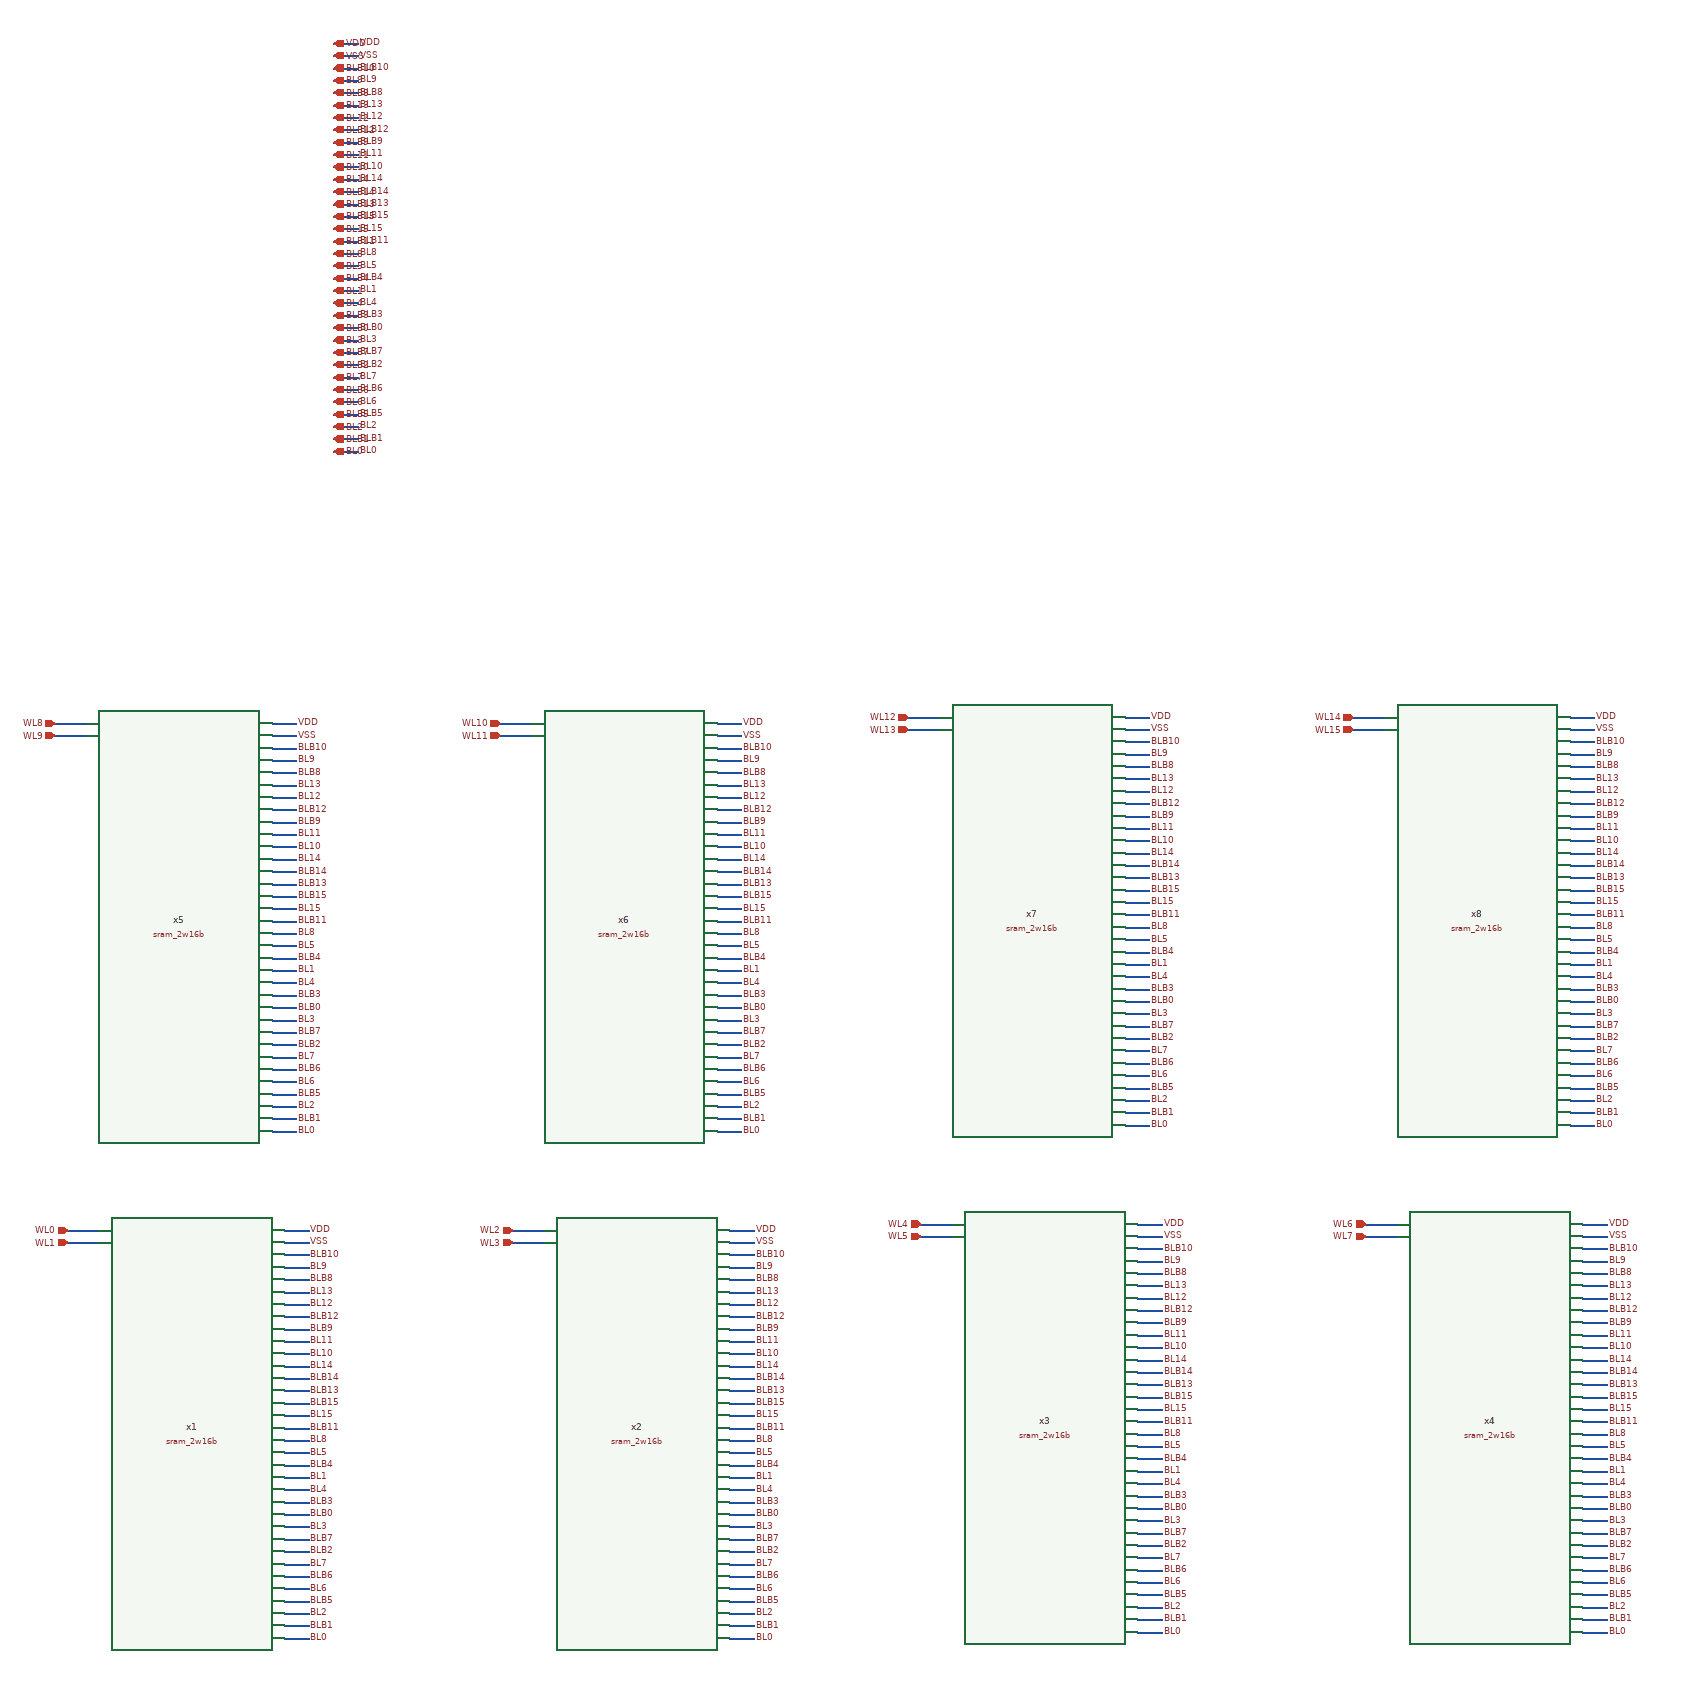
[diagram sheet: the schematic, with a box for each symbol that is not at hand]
v {xschem version=3.4.8RC file_version=1.3}
G {}
K {}
V {}
S {}
F {}
E {}
N 90 -730 140 -730 {lab=WL0}
N 90 -710 140 -710 {lab=WL1}
N 440 -730 480 -730 {lab=VDD}
N 440 -710 480 -710 {lab=VSS}
N 440 -690 480 -690 {lab=BLB10}
N 440 -670 480 -670 {lab=BL9}
N 440 -650 480 -650 {lab=BLB8}
N 440 -630 480 -630 {lab=BL13}
N 440 -610 480 -610 {lab=BL12}
N 440 -590 480 -590 {lab=BLB12}
N 440 -570 480 -570 {lab=BLB9}
N 440 -550 480 -550 {lab=BL11}
N 440 -530 480 -530 {lab=BL10}
N 440 -510 480 -510 {lab=BL14}
N 440 -490 480 -490 {lab=BLB14}
N 440 -470 480 -470 {lab=BLB13}
N 440 -450 480 -450 {lab=BLB15}
N 440 -430 480 -430 {lab=BL15}
N 440 -410 480 -410 {lab=BLB11}
N 440 -390 480 -390 {lab=BL8}
N 440 -370 480 -370 {lab=BL5}
N 440 -350 480 -350 {lab=BLB4}
N 440 -330 480 -330 {lab=BL1}
N 440 -310 480 -310 {lab=BL4}
N 440 -290 480 -290 {lab=BLB3}
N 440 -270 480 -270 {lab=BLB0}
N 440 -250 480 -250 {lab=BL3}
N 440 -230 480 -230 {lab=BLB7}
N 440 -210 480 -210 {lab=BLB2}
N 440 -190 480 -190 {lab=BL7}
N 440 -170 480 -170 {lab=BLB6}
N 440 -150 480 -150 {lab=BL6}
N 440 -130 480 -130 {lab=BLB5}
N 440 -110 480 -110 {lab=BL2}
N 440 -90 480 -90 {lab=BLB1}
N 440 -70 480 -70 {lab=BL0}
N 810 -730 860 -730 {lab=WL2}
N 810 -710 860 -710 {lab=WL3}
N 1160 -730 1200 -730 {lab=VDD}
N 1160 -710 1200 -710 {lab=VSS}
N 1160 -690 1200 -690 {lab=BLB10}
N 1160 -670 1200 -670 {lab=BL9}
N 1160 -650 1200 -650 {lab=BLB8}
N 1160 -630 1200 -630 {lab=BL13}
N 1160 -610 1200 -610 {lab=BL12}
N 1160 -590 1200 -590 {lab=BLB12}
N 1160 -570 1200 -570 {lab=BLB9}
N 1160 -550 1200 -550 {lab=BL11}
N 1160 -530 1200 -530 {lab=BL10}
N 1160 -510 1200 -510 {lab=BL14}
N 1160 -490 1200 -490 {lab=BLB14}
N 1160 -470 1200 -470 {lab=BLB13}
N 1160 -450 1200 -450 {lab=BLB15}
N 1160 -430 1200 -430 {lab=BL15}
N 1160 -410 1200 -410 {lab=BLB11}
N 1160 -390 1200 -390 {lab=BL8}
N 1160 -370 1200 -370 {lab=BL5}
N 1160 -350 1200 -350 {lab=BLB4}
N 1160 -330 1200 -330 {lab=BL1}
N 1160 -310 1200 -310 {lab=BL4}
N 1160 -290 1200 -290 {lab=BLB3}
N 1160 -270 1200 -270 {lab=BLB0}
N 1160 -250 1200 -250 {lab=BL3}
N 1160 -230 1200 -230 {lab=BLB7}
N 1160 -210 1200 -210 {lab=BLB2}
N 1160 -190 1200 -190 {lab=BL7}
N 1160 -170 1200 -170 {lab=BLB6}
N 1160 -150 1200 -150 {lab=BL6}
N 1160 -130 1200 -130 {lab=BLB5}
N 1160 -110 1200 -110 {lab=BL2}
N 1160 -90 1200 -90 {lab=BLB1}
N 1160 -70 1200 -70 {lab=BL0}
N 1470 -740 1520 -740 {lab=WL4}
N 1470 -720 1520 -720 {lab=WL5}
N 1820 -740 1860 -740 {lab=VDD}
N 1820 -720 1860 -720 {lab=VSS}
N 1820 -700 1860 -700 {lab=BLB10}
N 1820 -680 1860 -680 {lab=BL9}
N 1820 -660 1860 -660 {lab=BLB8}
N 1820 -640 1860 -640 {lab=BL13}
N 1820 -620 1860 -620 {lab=BL12}
N 1820 -600 1860 -600 {lab=BLB12}
N 1820 -580 1860 -580 {lab=BLB9}
N 1820 -560 1860 -560 {lab=BL11}
N 1820 -540 1860 -540 {lab=BL10}
N 1820 -520 1860 -520 {lab=BL14}
N 1820 -500 1860 -500 {lab=BLB14}
N 1820 -480 1860 -480 {lab=BLB13}
N 1820 -460 1860 -460 {lab=BLB15}
N 1820 -440 1860 -440 {lab=BL15}
N 1820 -420 1860 -420 {lab=BLB11}
N 1820 -400 1860 -400 {lab=BL8}
N 1820 -380 1860 -380 {lab=BL5}
N 1820 -360 1860 -360 {lab=BLB4}
N 1820 -340 1860 -340 {lab=BL1}
N 1820 -320 1860 -320 {lab=BL4}
N 1820 -300 1860 -300 {lab=BLB3}
N 1820 -280 1860 -280 {lab=BLB0}
N 1820 -260 1860 -260 {lab=BL3}
N 1820 -240 1860 -240 {lab=BLB7}
N 1820 -220 1860 -220 {lab=BLB2}
N 1820 -200 1860 -200 {lab=BL7}
N 1820 -180 1860 -180 {lab=BLB6}
N 1820 -160 1860 -160 {lab=BL6}
N 1820 -140 1860 -140 {lab=BLB5}
N 1820 -120 1860 -120 {lab=BL2}
N 1820 -100 1860 -100 {lab=BLB1}
N 1820 -80 1860 -80 {lab=BL0}
N 2190 -740 2240 -740 {lab=WL6}
N 2190 -720 2240 -720 {lab=WL1}
N 2540 -740 2580 -740 {lab=VDD}
N 2540 -720 2580 -720 {lab=VSS}
N 2540 -700 2580 -700 {lab=BLB10}
N 2540 -680 2580 -680 {lab=BL9}
N 2540 -660 2580 -660 {lab=BLB8}
N 2540 -640 2580 -640 {lab=BL13}
N 2540 -620 2580 -620 {lab=BL12}
N 2540 -600 2580 -600 {lab=BLB12}
N 2540 -580 2580 -580 {lab=BLB9}
N 2540 -560 2580 -560 {lab=BL11}
N 2540 -540 2580 -540 {lab=BL10}
N 2540 -520 2580 -520 {lab=BL14}
N 2540 -500 2580 -500 {lab=BLB14}
N 2540 -480 2580 -480 {lab=BLB13}
N 2540 -460 2580 -460 {lab=BLB15}
N 2540 -440 2580 -440 {lab=BL15}
N 2540 -420 2580 -420 {lab=BLB11}
N 2540 -400 2580 -400 {lab=BL8}
N 2540 -380 2580 -380 {lab=BL5}
N 2540 -360 2580 -360 {lab=BLB4}
N 2540 -340 2580 -340 {lab=BL1}
N 2540 -320 2580 -320 {lab=BL4}
N 2540 -300 2580 -300 {lab=BLB3}
N 2540 -280 2580 -280 {lab=BLB0}
N 2540 -260 2580 -260 {lab=BL3}
N 2540 -240 2580 -240 {lab=BLB7}
N 2540 -220 2580 -220 {lab=BLB2}
N 2540 -200 2580 -200 {lab=BL7}
N 2540 -180 2580 -180 {lab=BLB6}
N 2540 -160 2580 -160 {lab=BL6}
N 2540 -140 2580 -140 {lab=BLB5}
N 2540 -120 2580 -120 {lab=BL2}
N 2540 -100 2580 -100 {lab=BLB1}
N 2540 -80 2580 -80 {lab=BL0}
N 70 -1550 120 -1550 {lab=WL0}
N 70 -1530 120 -1530 {lab=WL1}
N 420 -1550 460 -1550 {lab=VDD}
N 420 -1530 460 -1530 {lab=VSS}
N 420 -1510 460 -1510 {lab=BLB10}
N 420 -1490 460 -1490 {lab=BL9}
N 420 -1470 460 -1470 {lab=BLB8}
N 420 -1450 460 -1450 {lab=BL13}
N 420 -1430 460 -1430 {lab=BL12}
N 420 -1410 460 -1410 {lab=BLB12}
N 420 -1390 460 -1390 {lab=BLB9}
N 420 -1370 460 -1370 {lab=BL11}
N 420 -1350 460 -1350 {lab=BL10}
N 420 -1330 460 -1330 {lab=BL14}
N 420 -1310 460 -1310 {lab=BLB14}
N 420 -1290 460 -1290 {lab=BLB13}
N 420 -1270 460 -1270 {lab=BLB15}
N 420 -1250 460 -1250 {lab=BL15}
N 420 -1230 460 -1230 {lab=BLB11}
N 420 -1210 460 -1210 {lab=BL8}
N 420 -1190 460 -1190 {lab=BL5}
N 420 -1170 460 -1170 {lab=BLB4}
N 420 -1150 460 -1150 {lab=BL1}
N 420 -1130 460 -1130 {lab=BL4}
N 420 -1110 460 -1110 {lab=BLB3}
N 420 -1090 460 -1090 {lab=BLB0}
N 420 -1070 460 -1070 {lab=BL3}
N 420 -1050 460 -1050 {lab=BLB7}
N 420 -1030 460 -1030 {lab=BLB2}
N 420 -1010 460 -1010 {lab=BL7}
N 420 -990 460 -990 {lab=BLB6}
N 420 -970 460 -970 {lab=BL6}
N 420 -950 460 -950 {lab=BLB5}
N 420 -930 460 -930 {lab=BL2}
N 420 -910 460 -910 {lab=BLB1}
N 420 -890 460 -890 {lab=BL0}
N 790 -1550 840 -1550 {lab=WL2}
N 790 -1530 840 -1530 {lab=WL3}
N 1140 -1550 1180 -1550 {lab=VDD}
N 1140 -1530 1180 -1530 {lab=VSS}
N 1140 -1510 1180 -1510 {lab=BLB10}
N 1140 -1490 1180 -1490 {lab=BL9}
N 1140 -1470 1180 -1470 {lab=BLB8}
N 1140 -1450 1180 -1450 {lab=BL13}
N 1140 -1430 1180 -1430 {lab=BL12}
N 1140 -1410 1180 -1410 {lab=BLB12}
N 1140 -1390 1180 -1390 {lab=BLB9}
N 1140 -1370 1180 -1370 {lab=BL11}
N 1140 -1350 1180 -1350 {lab=BL10}
N 1140 -1330 1180 -1330 {lab=BL14}
N 1140 -1310 1180 -1310 {lab=BLB14}
N 1140 -1290 1180 -1290 {lab=BLB13}
N 1140 -1270 1180 -1270 {lab=BLB15}
N 1140 -1250 1180 -1250 {lab=BL15}
N 1140 -1230 1180 -1230 {lab=BLB11}
N 1140 -1210 1180 -1210 {lab=BL8}
N 1140 -1190 1180 -1190 {lab=BL5}
N 1140 -1170 1180 -1170 {lab=BLB4}
N 1140 -1150 1180 -1150 {lab=BL1}
N 1140 -1130 1180 -1130 {lab=BL4}
N 1140 -1110 1180 -1110 {lab=BLB3}
N 1140 -1090 1180 -1090 {lab=BLB0}
N 1140 -1070 1180 -1070 {lab=BL3}
N 1140 -1050 1180 -1050 {lab=BLB7}
N 1140 -1030 1180 -1030 {lab=BLB2}
N 1140 -1010 1180 -1010 {lab=BL7}
N 1140 -990 1180 -990 {lab=BLB6}
N 1140 -970 1180 -970 {lab=BL6}
N 1140 -950 1180 -950 {lab=BLB5}
N 1140 -930 1180 -930 {lab=BL2}
N 1140 -910 1180 -910 {lab=BLB1}
N 1140 -890 1180 -890 {lab=BL0}
N 1450 -1560 1500 -1560 {lab=WL4}
N 1450 -1540 1500 -1540 {lab=WL5}
N 1800 -1560 1840 -1560 {lab=VDD}
N 1800 -1540 1840 -1540 {lab=VSS}
N 1800 -1520 1840 -1520 {lab=BLB10}
N 1800 -1500 1840 -1500 {lab=BL9}
N 1800 -1480 1840 -1480 {lab=BLB8}
N 1800 -1460 1840 -1460 {lab=BL13}
N 1800 -1440 1840 -1440 {lab=BL12}
N 1800 -1420 1840 -1420 {lab=BLB12}
N 1800 -1400 1840 -1400 {lab=BLB9}
N 1800 -1380 1840 -1380 {lab=BL11}
N 1800 -1360 1840 -1360 {lab=BL10}
N 1800 -1340 1840 -1340 {lab=BL14}
N 1800 -1320 1840 -1320 {lab=BLB14}
N 1800 -1300 1840 -1300 {lab=BLB13}
N 1800 -1280 1840 -1280 {lab=BLB15}
N 1800 -1260 1840 -1260 {lab=BL15}
N 1800 -1240 1840 -1240 {lab=BLB11}
N 1800 -1220 1840 -1220 {lab=BL8}
N 1800 -1200 1840 -1200 {lab=BL5}
N 1800 -1180 1840 -1180 {lab=BLB4}
N 1800 -1160 1840 -1160 {lab=BL1}
N 1800 -1140 1840 -1140 {lab=BL4}
N 1800 -1120 1840 -1120 {lab=BLB3}
N 1800 -1100 1840 -1100 {lab=BLB0}
N 1800 -1080 1840 -1080 {lab=BL3}
N 1800 -1060 1840 -1060 {lab=BLB7}
N 1800 -1040 1840 -1040 {lab=BLB2}
N 1800 -1020 1840 -1020 {lab=BL7}
N 1800 -1000 1840 -1000 {lab=BLB6}
N 1800 -980 1840 -980 {lab=BL6}
N 1800 -960 1840 -960 {lab=BLB5}
N 1800 -940 1840 -940 {lab=BL2}
N 1800 -920 1840 -920 {lab=BLB1}
N 1800 -900 1840 -900 {lab=BL0}
N 2170 -1560 2220 -1560 {lab=WL6}
N 2170 -1540 2220 -1540 {lab=WL1}
N 2520 -1560 2560 -1560 {lab=VDD}
N 2520 -1540 2560 -1540 {lab=VSS}
N 2520 -1520 2560 -1520 {lab=BLB10}
N 2520 -1500 2560 -1500 {lab=BL9}
N 2520 -1480 2560 -1480 {lab=BLB8}
N 2520 -1460 2560 -1460 {lab=BL13}
N 2520 -1440 2560 -1440 {lab=BL12}
N 2520 -1420 2560 -1420 {lab=BLB12}
N 2520 -1400 2560 -1400 {lab=BLB9}
N 2520 -1380 2560 -1380 {lab=BL11}
N 2520 -1360 2560 -1360 {lab=BL10}
N 2520 -1340 2560 -1340 {lab=BL14}
N 2520 -1320 2560 -1320 {lab=BLB14}
N 2520 -1300 2560 -1300 {lab=BLB13}
N 2520 -1280 2560 -1280 {lab=BLB15}
N 2520 -1260 2560 -1260 {lab=BL15}
N 2520 -1240 2560 -1240 {lab=BLB11}
N 2520 -1220 2560 -1220 {lab=BL8}
N 2520 -1200 2560 -1200 {lab=BL5}
N 2520 -1180 2560 -1180 {lab=BLB4}
N 2520 -1160 2560 -1160 {lab=BL1}
N 2520 -1140 2560 -1140 {lab=BL4}
N 2520 -1120 2560 -1120 {lab=BLB3}
N 2520 -1100 2560 -1100 {lab=BLB0}
N 2520 -1080 2560 -1080 {lab=BL3}
N 2520 -1060 2560 -1060 {lab=BLB7}
N 2520 -1040 2560 -1040 {lab=BLB2}
N 2520 -1020 2560 -1020 {lab=BL7}
N 2520 -1000 2560 -1000 {lab=BLB6}
N 2520 -980 2560 -980 {lab=BL6}
N 2520 -960 2560 -960 {lab=BLB5}
N 2520 -940 2560 -940 {lab=BL2}
N 2520 -920 2560 -920 {lab=BLB1}
N 2520 -900 2560 -900 {lab=BL0}
N 520 -2650 560 -2650 {lab=VDD}
N 520 -2630 560 -2630 {lab=VSS}
N 520 -2610 560 -2610 {lab=BLB10}
N 520 -2590 560 -2590 {lab=BL9}
N 520 -2570 560 -2570 {lab=BLB8}
N 520 -2550 560 -2550 {lab=BL13}
N 520 -2530 560 -2530 {lab=BL12}
N 520 -2510 560 -2510 {lab=BLB12}
N 520 -2490 560 -2490 {lab=BLB9}
N 520 -2470 560 -2470 {lab=BL11}
N 520 -2450 560 -2450 {lab=BL10}
N 520 -2430 560 -2430 {lab=BL14}
N 520 -2410 560 -2410 {lab=BLB14}
N 520 -2390 560 -2390 {lab=BLB13}
N 520 -2370 560 -2370 {lab=BLB15}
N 520 -2350 560 -2350 {lab=BL15}
N 520 -2330 560 -2330 {lab=BLB11}
N 520 -2310 560 -2310 {lab=BL8}
N 520 -2290 560 -2290 {lab=BL5}
N 520 -2270 560 -2270 {lab=BLB4}
N 520 -2250 560 -2250 {lab=BL1}
N 520 -2230 560 -2230 {lab=BL4}
N 520 -2210 560 -2210 {lab=BLB3}
N 520 -2190 560 -2190 {lab=BLB0}
N 520 -2170 560 -2170 {lab=BL3}
N 520 -2150 560 -2150 {lab=BLB7}
N 520 -2130 560 -2130 {lab=BLB2}
N 520 -2110 560 -2110 {lab=BL7}
N 520 -2090 560 -2090 {lab=BLB6}
N 520 -2070 560 -2070 {lab=BL6}
N 520 -2050 560 -2050 {lab=BLB5}
N 520 -2030 560 -2030 {lab=BL2}
N 520 -2010 560 -2010 {lab=BLB1}
N 520 -1990 560 -1990 {lab=BL0}
C {sram_2w16b.sym} 290 -400 0 0 {name=x1}
C {devices/ipin.sym} 90 -730 0 0 {name=p1 lab=WL0}
C {devices/ipin.sym} 90 -710 0 0 {name=p2 lab=WL1}
C {devices/lab_pin.sym} 480 -730 0 1 {name=p3 sig_type=std_logic lab=VDD}
C {devices/lab_pin.sym} 480 -710 0 1 {name=p4 sig_type=std_logic lab=VSS}
C {devices/lab_pin.sym} 480 -690 0 1 {name=p5 sig_type=std_logic lab=BLB10}
C {devices/lab_pin.sym} 480 -670 0 1 {name=p6 sig_type=std_logic lab=BL9}
C {devices/lab_pin.sym} 480 -650 0 1 {name=p7 sig_type=std_logic lab=BLB8}
C {devices/lab_pin.sym} 480 -630 0 1 {name=p8 sig_type=std_logic lab=BL13}
C {devices/lab_pin.sym} 480 -610 0 1 {name=p9 sig_type=std_logic lab=BL12}
C {devices/lab_pin.sym} 480 -590 0 1 {name=p10 sig_type=std_logic lab=BLB12}
C {devices/lab_pin.sym} 480 -570 0 1 {name=p11 sig_type=std_logic lab=BLB9}
C {devices/lab_pin.sym} 480 -550 0 1 {name=p12 sig_type=std_logic lab=BL11}
C {devices/lab_pin.sym} 480 -530 0 1 {name=p13 sig_type=std_logic lab=BL10}
C {devices/lab_pin.sym} 480 -510 0 1 {name=p14 sig_type=std_logic lab=BL14}
C {devices/lab_pin.sym} 480 -490 0 1 {name=p15 sig_type=std_logic lab=BLB14}
C {devices/lab_pin.sym} 480 -470 0 1 {name=p16 sig_type=std_logic lab=BLB13}
C {devices/lab_pin.sym} 480 -450 0 1 {name=p17 sig_type=std_logic lab=BLB15}
C {devices/lab_pin.sym} 480 -430 0 1 {name=p18 sig_type=std_logic lab=BL15}
C {devices/lab_pin.sym} 480 -410 0 1 {name=p19 sig_type=std_logic lab=BLB11}
C {devices/lab_pin.sym} 480 -390 0 1 {name=p20 sig_type=std_logic lab=BL8}
C {devices/lab_pin.sym} 480 -370 0 1 {name=p21 sig_type=std_logic lab=BL5}
C {devices/lab_pin.sym} 480 -350 0 1 {name=p22 sig_type=std_logic lab=BLB4}
C {devices/lab_pin.sym} 480 -330 0 1 {name=p23 sig_type=std_logic lab=BL1}
C {devices/lab_pin.sym} 480 -310 0 1 {name=p24 sig_type=std_logic lab=BL4}
C {devices/lab_pin.sym} 480 -290 0 1 {name=p25 sig_type=std_logic lab=BLB3}
C {devices/lab_pin.sym} 480 -270 0 1 {name=p26 sig_type=std_logic lab=BLB0}
C {devices/lab_pin.sym} 480 -250 0 1 {name=p27 sig_type=std_logic lab=BL3}
C {devices/lab_pin.sym} 480 -230 0 1 {name=p28 sig_type=std_logic lab=BLB7}
C {devices/lab_pin.sym} 480 -210 0 1 {name=p29 sig_type=std_logic lab=BLB2}
C {devices/lab_pin.sym} 480 -190 0 1 {name=p30 sig_type=std_logic lab=BL7}
C {devices/lab_pin.sym} 480 -170 0 1 {name=p31 sig_type=std_logic lab=BLB6}
C {devices/lab_pin.sym} 480 -150 0 1 {name=p32 sig_type=std_logic lab=BL6}
C {devices/lab_pin.sym} 480 -130 0 1 {name=p33 sig_type=std_logic lab=BLB5}
C {devices/lab_pin.sym} 480 -110 0 1 {name=p34 sig_type=std_logic lab=BL2}
C {devices/lab_pin.sym} 480 -90 0 1 {name=p35 sig_type=std_logic lab=BLB1}
C {devices/lab_pin.sym} 480 -70 0 1 {name=p36 sig_type=std_logic lab=BL0}
C {sram_2w16b.sym} 1010 -400 0 0 {name=x2}
C {devices/ipin.sym} 810 -730 0 0 {name=p37 lab=WL2}
C {devices/ipin.sym} 810 -710 0 0 {name=p38 lab=WL3}
C {devices/lab_pin.sym} 1200 -730 0 1 {name=p39 sig_type=std_logic lab=VDD}
C {devices/lab_pin.sym} 1200 -710 0 1 {name=p40 sig_type=std_logic lab=VSS}
C {devices/lab_pin.sym} 1200 -690 0 1 {name=p41 sig_type=std_logic lab=BLB10}
C {devices/lab_pin.sym} 1200 -670 0 1 {name=p42 sig_type=std_logic lab=BL9}
C {devices/lab_pin.sym} 1200 -650 0 1 {name=p43 sig_type=std_logic lab=BLB8}
C {devices/lab_pin.sym} 1200 -630 0 1 {name=p44 sig_type=std_logic lab=BL13}
C {devices/lab_pin.sym} 1200 -610 0 1 {name=p45 sig_type=std_logic lab=BL12}
C {devices/lab_pin.sym} 1200 -590 0 1 {name=p46 sig_type=std_logic lab=BLB12}
C {devices/lab_pin.sym} 1200 -570 0 1 {name=p47 sig_type=std_logic lab=BLB9}
C {devices/lab_pin.sym} 1200 -550 0 1 {name=p48 sig_type=std_logic lab=BL11}
C {devices/lab_pin.sym} 1200 -530 0 1 {name=p49 sig_type=std_logic lab=BL10}
C {devices/lab_pin.sym} 1200 -510 0 1 {name=p50 sig_type=std_logic lab=BL14}
C {devices/lab_pin.sym} 1200 -490 0 1 {name=p51 sig_type=std_logic lab=BLB14}
C {devices/lab_pin.sym} 1200 -470 0 1 {name=p52 sig_type=std_logic lab=BLB13}
C {devices/lab_pin.sym} 1200 -450 0 1 {name=p53 sig_type=std_logic lab=BLB15}
C {devices/lab_pin.sym} 1200 -430 0 1 {name=p54 sig_type=std_logic lab=BL15}
C {devices/lab_pin.sym} 1200 -410 0 1 {name=p55 sig_type=std_logic lab=BLB11}
C {devices/lab_pin.sym} 1200 -390 0 1 {name=p56 sig_type=std_logic lab=BL8}
C {devices/lab_pin.sym} 1200 -370 0 1 {name=p57 sig_type=std_logic lab=BL5}
C {devices/lab_pin.sym} 1200 -350 0 1 {name=p58 sig_type=std_logic lab=BLB4}
C {devices/lab_pin.sym} 1200 -330 0 1 {name=p59 sig_type=std_logic lab=BL1}
C {devices/lab_pin.sym} 1200 -310 0 1 {name=p60 sig_type=std_logic lab=BL4}
C {devices/lab_pin.sym} 1200 -290 0 1 {name=p61 sig_type=std_logic lab=BLB3}
C {devices/lab_pin.sym} 1200 -270 0 1 {name=p62 sig_type=std_logic lab=BLB0}
C {devices/lab_pin.sym} 1200 -250 0 1 {name=p63 sig_type=std_logic lab=BL3}
C {devices/lab_pin.sym} 1200 -230 0 1 {name=p64 sig_type=std_logic lab=BLB7}
C {devices/lab_pin.sym} 1200 -210 0 1 {name=p65 sig_type=std_logic lab=BLB2}
C {devices/lab_pin.sym} 1200 -190 0 1 {name=p66 sig_type=std_logic lab=BL7}
C {devices/lab_pin.sym} 1200 -170 0 1 {name=p67 sig_type=std_logic lab=BLB6}
C {devices/lab_pin.sym} 1200 -150 0 1 {name=p68 sig_type=std_logic lab=BL6}
C {devices/lab_pin.sym} 1200 -130 0 1 {name=p69 sig_type=std_logic lab=BLB5}
C {devices/lab_pin.sym} 1200 -110 0 1 {name=p70 sig_type=std_logic lab=BL2}
C {devices/lab_pin.sym} 1200 -90 0 1 {name=p71 sig_type=std_logic lab=BLB1}
C {devices/lab_pin.sym} 1200 -70 0 1 {name=p72 sig_type=std_logic lab=BL0}
C {sram_2w16b.sym} 1670 -410 0 0 {name=x3}
C {devices/ipin.sym} 1470 -740 0 0 {name=p73 lab=WL4}
C {devices/ipin.sym} 1470 -720 0 0 {name=p74 lab=WL5}
C {devices/lab_pin.sym} 1860 -740 0 1 {name=p75 sig_type=std_logic lab=VDD}
C {devices/lab_pin.sym} 1860 -720 0 1 {name=p76 sig_type=std_logic lab=VSS}
C {devices/lab_pin.sym} 1860 -700 0 1 {name=p77 sig_type=std_logic lab=BLB10}
C {devices/lab_pin.sym} 1860 -680 0 1 {name=p78 sig_type=std_logic lab=BL9}
C {devices/lab_pin.sym} 1860 -660 0 1 {name=p79 sig_type=std_logic lab=BLB8}
C {devices/lab_pin.sym} 1860 -640 0 1 {name=p80 sig_type=std_logic lab=BL13}
C {devices/lab_pin.sym} 1860 -620 0 1 {name=p81 sig_type=std_logic lab=BL12}
C {devices/lab_pin.sym} 1860 -600 0 1 {name=p82 sig_type=std_logic lab=BLB12}
C {devices/lab_pin.sym} 1860 -580 0 1 {name=p83 sig_type=std_logic lab=BLB9}
C {devices/lab_pin.sym} 1860 -560 0 1 {name=p84 sig_type=std_logic lab=BL11}
C {devices/lab_pin.sym} 1860 -540 0 1 {name=p85 sig_type=std_logic lab=BL10}
C {devices/lab_pin.sym} 1860 -520 0 1 {name=p86 sig_type=std_logic lab=BL14}
C {devices/lab_pin.sym} 1860 -500 0 1 {name=p87 sig_type=std_logic lab=BLB14}
C {devices/lab_pin.sym} 1860 -480 0 1 {name=p88 sig_type=std_logic lab=BLB13}
C {devices/lab_pin.sym} 1860 -460 0 1 {name=p89 sig_type=std_logic lab=BLB15}
C {devices/lab_pin.sym} 1860 -440 0 1 {name=p90 sig_type=std_logic lab=BL15}
C {devices/lab_pin.sym} 1860 -420 0 1 {name=p91 sig_type=std_logic lab=BLB11}
C {devices/lab_pin.sym} 1860 -400 0 1 {name=p92 sig_type=std_logic lab=BL8}
C {devices/lab_pin.sym} 1860 -380 0 1 {name=p93 sig_type=std_logic lab=BL5}
C {devices/lab_pin.sym} 1860 -360 0 1 {name=p94 sig_type=std_logic lab=BLB4}
C {devices/lab_pin.sym} 1860 -340 0 1 {name=p95 sig_type=std_logic lab=BL1}
C {devices/lab_pin.sym} 1860 -320 0 1 {name=p96 sig_type=std_logic lab=BL4}
C {devices/lab_pin.sym} 1860 -300 0 1 {name=p97 sig_type=std_logic lab=BLB3}
C {devices/lab_pin.sym} 1860 -280 0 1 {name=p98 sig_type=std_logic lab=BLB0}
C {devices/lab_pin.sym} 1860 -260 0 1 {name=p99 sig_type=std_logic lab=BL3}
C {devices/lab_pin.sym} 1860 -240 0 1 {name=p100 sig_type=std_logic lab=BLB7}
C {devices/lab_pin.sym} 1860 -220 0 1 {name=p101 sig_type=std_logic lab=BLB2}
C {devices/lab_pin.sym} 1860 -200 0 1 {name=p102 sig_type=std_logic lab=BL7}
C {devices/lab_pin.sym} 1860 -180 0 1 {name=p103 sig_type=std_logic lab=BLB6}
C {devices/lab_pin.sym} 1860 -160 0 1 {name=p104 sig_type=std_logic lab=BL6}
C {devices/lab_pin.sym} 1860 -140 0 1 {name=p105 sig_type=std_logic lab=BLB5}
C {devices/lab_pin.sym} 1860 -120 0 1 {name=p106 sig_type=std_logic lab=BL2}
C {devices/lab_pin.sym} 1860 -100 0 1 {name=p107 sig_type=std_logic lab=BLB1}
C {devices/lab_pin.sym} 1860 -80 0 1 {name=p108 sig_type=std_logic lab=BL0}
C {sram_2w16b.sym} 2390 -410 0 0 {name=x4}
C {devices/ipin.sym} 2190 -740 0 0 {name=p109 lab=WL6}
C {devices/ipin.sym} 2190 -720 0 0 {name=p110 lab=WL7}
C {devices/lab_pin.sym} 2580 -740 0 1 {name=p111 sig_type=std_logic lab=VDD}
C {devices/lab_pin.sym} 2580 -720 0 1 {name=p112 sig_type=std_logic lab=VSS}
C {devices/lab_pin.sym} 2580 -700 0 1 {name=p113 sig_type=std_logic lab=BLB10}
C {devices/lab_pin.sym} 2580 -680 0 1 {name=p114 sig_type=std_logic lab=BL9}
C {devices/lab_pin.sym} 2580 -660 0 1 {name=p115 sig_type=std_logic lab=BLB8}
C {devices/lab_pin.sym} 2580 -640 0 1 {name=p116 sig_type=std_logic lab=BL13}
C {devices/lab_pin.sym} 2580 -620 0 1 {name=p117 sig_type=std_logic lab=BL12}
C {devices/lab_pin.sym} 2580 -600 0 1 {name=p118 sig_type=std_logic lab=BLB12}
C {devices/lab_pin.sym} 2580 -580 0 1 {name=p119 sig_type=std_logic lab=BLB9}
C {devices/lab_pin.sym} 2580 -560 0 1 {name=p120 sig_type=std_logic lab=BL11}
C {devices/lab_pin.sym} 2580 -540 0 1 {name=p121 sig_type=std_logic lab=BL10}
C {devices/lab_pin.sym} 2580 -520 0 1 {name=p122 sig_type=std_logic lab=BL14}
C {devices/lab_pin.sym} 2580 -500 0 1 {name=p123 sig_type=std_logic lab=BLB14}
C {devices/lab_pin.sym} 2580 -480 0 1 {name=p124 sig_type=std_logic lab=BLB13}
C {devices/lab_pin.sym} 2580 -460 0 1 {name=p125 sig_type=std_logic lab=BLB15}
C {devices/lab_pin.sym} 2580 -440 0 1 {name=p126 sig_type=std_logic lab=BL15}
C {devices/lab_pin.sym} 2580 -420 0 1 {name=p127 sig_type=std_logic lab=BLB11}
C {devices/lab_pin.sym} 2580 -400 0 1 {name=p128 sig_type=std_logic lab=BL8}
C {devices/lab_pin.sym} 2580 -380 0 1 {name=p129 sig_type=std_logic lab=BL5}
C {devices/lab_pin.sym} 2580 -360 0 1 {name=p130 sig_type=std_logic lab=BLB4}
C {devices/lab_pin.sym} 2580 -340 0 1 {name=p131 sig_type=std_logic lab=BL1}
C {devices/lab_pin.sym} 2580 -320 0 1 {name=p132 sig_type=std_logic lab=BL4}
C {devices/lab_pin.sym} 2580 -300 0 1 {name=p133 sig_type=std_logic lab=BLB3}
C {devices/lab_pin.sym} 2580 -280 0 1 {name=p134 sig_type=std_logic lab=BLB0}
C {devices/lab_pin.sym} 2580 -260 0 1 {name=p135 sig_type=std_logic lab=BL3}
C {devices/lab_pin.sym} 2580 -240 0 1 {name=p136 sig_type=std_logic lab=BLB7}
C {devices/lab_pin.sym} 2580 -220 0 1 {name=p137 sig_type=std_logic lab=BLB2}
C {devices/lab_pin.sym} 2580 -200 0 1 {name=p138 sig_type=std_logic lab=BL7}
C {devices/lab_pin.sym} 2580 -180 0 1 {name=p139 sig_type=std_logic lab=BLB6}
C {devices/lab_pin.sym} 2580 -160 0 1 {name=p140 sig_type=std_logic lab=BL6}
C {devices/lab_pin.sym} 2580 -140 0 1 {name=p141 sig_type=std_logic lab=BLB5}
C {devices/lab_pin.sym} 2580 -120 0 1 {name=p142 sig_type=std_logic lab=BL2}
C {devices/lab_pin.sym} 2580 -100 0 1 {name=p143 sig_type=std_logic lab=BLB1}
C {devices/lab_pin.sym} 2580 -80 0 1 {name=p144 sig_type=std_logic lab=BL0}
C {sram_2w16b.sym} 270 -1220 0 0 {name=x5}
C {devices/ipin.sym} 70 -1550 0 0 {name=p145 lab=WL8}
C {devices/ipin.sym} 70 -1530 0 0 {name=p146 lab=WL9}
C {devices/lab_pin.sym} 460 -1550 0 1 {name=p147 sig_type=std_logic lab=VDD}
C {devices/lab_pin.sym} 460 -1530 0 1 {name=p148 sig_type=std_logic lab=VSS}
C {devices/lab_pin.sym} 460 -1510 0 1 {name=p149 sig_type=std_logic lab=BLB10}
C {devices/lab_pin.sym} 460 -1490 0 1 {name=p150 sig_type=std_logic lab=BL9}
C {devices/lab_pin.sym} 460 -1470 0 1 {name=p151 sig_type=std_logic lab=BLB8}
C {devices/lab_pin.sym} 460 -1450 0 1 {name=p152 sig_type=std_logic lab=BL13}
C {devices/lab_pin.sym} 460 -1430 0 1 {name=p153 sig_type=std_logic lab=BL12}
C {devices/lab_pin.sym} 460 -1410 0 1 {name=p154 sig_type=std_logic lab=BLB12}
C {devices/lab_pin.sym} 460 -1390 0 1 {name=p155 sig_type=std_logic lab=BLB9}
C {devices/lab_pin.sym} 460 -1370 0 1 {name=p156 sig_type=std_logic lab=BL11}
C {devices/lab_pin.sym} 460 -1350 0 1 {name=p157 sig_type=std_logic lab=BL10}
C {devices/lab_pin.sym} 460 -1330 0 1 {name=p158 sig_type=std_logic lab=BL14}
C {devices/lab_pin.sym} 460 -1310 0 1 {name=p159 sig_type=std_logic lab=BLB14}
C {devices/lab_pin.sym} 460 -1290 0 1 {name=p160 sig_type=std_logic lab=BLB13}
C {devices/lab_pin.sym} 460 -1270 0 1 {name=p161 sig_type=std_logic lab=BLB15}
C {devices/lab_pin.sym} 460 -1250 0 1 {name=p162 sig_type=std_logic lab=BL15}
C {devices/lab_pin.sym} 460 -1230 0 1 {name=p163 sig_type=std_logic lab=BLB11}
C {devices/lab_pin.sym} 460 -1210 0 1 {name=p164 sig_type=std_logic lab=BL8}
C {devices/lab_pin.sym} 460 -1190 0 1 {name=p165 sig_type=std_logic lab=BL5}
C {devices/lab_pin.sym} 460 -1170 0 1 {name=p166 sig_type=std_logic lab=BLB4}
C {devices/lab_pin.sym} 460 -1150 0 1 {name=p167 sig_type=std_logic lab=BL1}
C {devices/lab_pin.sym} 460 -1130 0 1 {name=p168 sig_type=std_logic lab=BL4}
C {devices/lab_pin.sym} 460 -1110 0 1 {name=p169 sig_type=std_logic lab=BLB3}
C {devices/lab_pin.sym} 460 -1090 0 1 {name=p170 sig_type=std_logic lab=BLB0}
C {devices/lab_pin.sym} 460 -1070 0 1 {name=p171 sig_type=std_logic lab=BL3}
C {devices/lab_pin.sym} 460 -1050 0 1 {name=p172 sig_type=std_logic lab=BLB7}
C {devices/lab_pin.sym} 460 -1030 0 1 {name=p173 sig_type=std_logic lab=BLB2}
C {devices/lab_pin.sym} 460 -1010 0 1 {name=p174 sig_type=std_logic lab=BL7}
C {devices/lab_pin.sym} 460 -990 0 1 {name=p175 sig_type=std_logic lab=BLB6}
C {devices/lab_pin.sym} 460 -970 0 1 {name=p176 sig_type=std_logic lab=BL6}
C {devices/lab_pin.sym} 460 -950 0 1 {name=p177 sig_type=std_logic lab=BLB5}
C {devices/lab_pin.sym} 460 -930 0 1 {name=p178 sig_type=std_logic lab=BL2}
C {devices/lab_pin.sym} 460 -910 0 1 {name=p179 sig_type=std_logic lab=BLB1}
C {devices/lab_pin.sym} 460 -890 0 1 {name=p180 sig_type=std_logic lab=BL0}
C {sram_2w16b.sym} 990 -1220 0 0 {name=x6}
C {devices/ipin.sym} 790 -1550 0 0 {name=p181 lab=WL10}
C {devices/ipin.sym} 790 -1530 0 0 {name=p182 lab=WL11}
C {devices/lab_pin.sym} 1180 -1550 0 1 {name=p183 sig_type=std_logic lab=VDD}
C {devices/lab_pin.sym} 1180 -1530 0 1 {name=p184 sig_type=std_logic lab=VSS}
C {devices/lab_pin.sym} 1180 -1510 0 1 {name=p185 sig_type=std_logic lab=BLB10}
C {devices/lab_pin.sym} 1180 -1490 0 1 {name=p186 sig_type=std_logic lab=BL9}
C {devices/lab_pin.sym} 1180 -1470 0 1 {name=p187 sig_type=std_logic lab=BLB8}
C {devices/lab_pin.sym} 1180 -1450 0 1 {name=p188 sig_type=std_logic lab=BL13}
C {devices/lab_pin.sym} 1180 -1430 0 1 {name=p189 sig_type=std_logic lab=BL12}
C {devices/lab_pin.sym} 1180 -1410 0 1 {name=p190 sig_type=std_logic lab=BLB12}
C {devices/lab_pin.sym} 1180 -1390 0 1 {name=p191 sig_type=std_logic lab=BLB9}
C {devices/lab_pin.sym} 1180 -1370 0 1 {name=p192 sig_type=std_logic lab=BL11}
C {devices/lab_pin.sym} 1180 -1350 0 1 {name=p193 sig_type=std_logic lab=BL10}
C {devices/lab_pin.sym} 1180 -1330 0 1 {name=p194 sig_type=std_logic lab=BL14}
C {devices/lab_pin.sym} 1180 -1310 0 1 {name=p195 sig_type=std_logic lab=BLB14}
C {devices/lab_pin.sym} 1180 -1290 0 1 {name=p196 sig_type=std_logic lab=BLB13}
C {devices/lab_pin.sym} 1180 -1270 0 1 {name=p197 sig_type=std_logic lab=BLB15}
C {devices/lab_pin.sym} 1180 -1250 0 1 {name=p198 sig_type=std_logic lab=BL15}
C {devices/lab_pin.sym} 1180 -1230 0 1 {name=p199 sig_type=std_logic lab=BLB11}
C {devices/lab_pin.sym} 1180 -1210 0 1 {name=p200 sig_type=std_logic lab=BL8}
C {devices/lab_pin.sym} 1180 -1190 0 1 {name=p201 sig_type=std_logic lab=BL5}
C {devices/lab_pin.sym} 1180 -1170 0 1 {name=p202 sig_type=std_logic lab=BLB4}
C {devices/lab_pin.sym} 1180 -1150 0 1 {name=p203 sig_type=std_logic lab=BL1}
C {devices/lab_pin.sym} 1180 -1130 0 1 {name=p204 sig_type=std_logic lab=BL4}
C {devices/lab_pin.sym} 1180 -1110 0 1 {name=p205 sig_type=std_logic lab=BLB3}
C {devices/lab_pin.sym} 1180 -1090 0 1 {name=p206 sig_type=std_logic lab=BLB0}
C {devices/lab_pin.sym} 1180 -1070 0 1 {name=p207 sig_type=std_logic lab=BL3}
C {devices/lab_pin.sym} 1180 -1050 0 1 {name=p208 sig_type=std_logic lab=BLB7}
C {devices/lab_pin.sym} 1180 -1030 0 1 {name=p209 sig_type=std_logic lab=BLB2}
C {devices/lab_pin.sym} 1180 -1010 0 1 {name=p210 sig_type=std_logic lab=BL7}
C {devices/lab_pin.sym} 1180 -990 0 1 {name=p211 sig_type=std_logic lab=BLB6}
C {devices/lab_pin.sym} 1180 -970 0 1 {name=p212 sig_type=std_logic lab=BL6}
C {devices/lab_pin.sym} 1180 -950 0 1 {name=p213 sig_type=std_logic lab=BLB5}
C {devices/lab_pin.sym} 1180 -930 0 1 {name=p214 sig_type=std_logic lab=BL2}
C {devices/lab_pin.sym} 1180 -910 0 1 {name=p215 sig_type=std_logic lab=BLB1}
C {devices/lab_pin.sym} 1180 -890 0 1 {name=p216 sig_type=std_logic lab=BL0}
C {sram_2w16b.sym} 1650 -1230 0 0 {name=x7}
C {devices/ipin.sym} 1450 -1560 0 0 {name=p217 lab=WL12}
C {devices/ipin.sym} 1450 -1540 0 0 {name=p218 lab=WL13}
C {devices/lab_pin.sym} 1840 -1560 0 1 {name=p219 sig_type=std_logic lab=VDD}
C {devices/lab_pin.sym} 1840 -1540 0 1 {name=p220 sig_type=std_logic lab=VSS}
C {devices/lab_pin.sym} 1840 -1520 0 1 {name=p221 sig_type=std_logic lab=BLB10}
C {devices/lab_pin.sym} 1840 -1500 0 1 {name=p222 sig_type=std_logic lab=BL9}
C {devices/lab_pin.sym} 1840 -1480 0 1 {name=p223 sig_type=std_logic lab=BLB8}
C {devices/lab_pin.sym} 1840 -1460 0 1 {name=p224 sig_type=std_logic lab=BL13}
C {devices/lab_pin.sym} 1840 -1440 0 1 {name=p225 sig_type=std_logic lab=BL12}
C {devices/lab_pin.sym} 1840 -1420 0 1 {name=p226 sig_type=std_logic lab=BLB12}
C {devices/lab_pin.sym} 1840 -1400 0 1 {name=p227 sig_type=std_logic lab=BLB9}
C {devices/lab_pin.sym} 1840 -1380 0 1 {name=p228 sig_type=std_logic lab=BL11}
C {devices/lab_pin.sym} 1840 -1360 0 1 {name=p229 sig_type=std_logic lab=BL10}
C {devices/lab_pin.sym} 1840 -1340 0 1 {name=p230 sig_type=std_logic lab=BL14}
C {devices/lab_pin.sym} 1840 -1320 0 1 {name=p231 sig_type=std_logic lab=BLB14}
C {devices/lab_pin.sym} 1840 -1300 0 1 {name=p232 sig_type=std_logic lab=BLB13}
C {devices/lab_pin.sym} 1840 -1280 0 1 {name=p233 sig_type=std_logic lab=BLB15}
C {devices/lab_pin.sym} 1840 -1260 0 1 {name=p234 sig_type=std_logic lab=BL15}
C {devices/lab_pin.sym} 1840 -1240 0 1 {name=p235 sig_type=std_logic lab=BLB11}
C {devices/lab_pin.sym} 1840 -1220 0 1 {name=p236 sig_type=std_logic lab=BL8}
C {devices/lab_pin.sym} 1840 -1200 0 1 {name=p237 sig_type=std_logic lab=BL5}
C {devices/lab_pin.sym} 1840 -1180 0 1 {name=p238 sig_type=std_logic lab=BLB4}
C {devices/lab_pin.sym} 1840 -1160 0 1 {name=p239 sig_type=std_logic lab=BL1}
C {devices/lab_pin.sym} 1840 -1140 0 1 {name=p240 sig_type=std_logic lab=BL4}
C {devices/lab_pin.sym} 1840 -1120 0 1 {name=p241 sig_type=std_logic lab=BLB3}
C {devices/lab_pin.sym} 1840 -1100 0 1 {name=p242 sig_type=std_logic lab=BLB0}
C {devices/lab_pin.sym} 1840 -1080 0 1 {name=p243 sig_type=std_logic lab=BL3}
C {devices/lab_pin.sym} 1840 -1060 0 1 {name=p244 sig_type=std_logic lab=BLB7}
C {devices/lab_pin.sym} 1840 -1040 0 1 {name=p245 sig_type=std_logic lab=BLB2}
C {devices/lab_pin.sym} 1840 -1020 0 1 {name=p246 sig_type=std_logic lab=BL7}
C {devices/lab_pin.sym} 1840 -1000 0 1 {name=p247 sig_type=std_logic lab=BLB6}
C {devices/lab_pin.sym} 1840 -980 0 1 {name=p248 sig_type=std_logic lab=BL6}
C {devices/lab_pin.sym} 1840 -960 0 1 {name=p249 sig_type=std_logic lab=BLB5}
C {devices/lab_pin.sym} 1840 -940 0 1 {name=p250 sig_type=std_logic lab=BL2}
C {devices/lab_pin.sym} 1840 -920 0 1 {name=p251 sig_type=std_logic lab=BLB1}
C {devices/lab_pin.sym} 1840 -900 0 1 {name=p252 sig_type=std_logic lab=BL0}
C {sram_2w16b.sym} 2370 -1230 0 0 {name=x8}
C {devices/ipin.sym} 2170 -1560 0 0 {name=p253 lab=WL14}
C {devices/ipin.sym} 2170 -1540 0 0 {name=p254 lab=WL15}
C {devices/lab_pin.sym} 2560 -1560 0 1 {name=p255 sig_type=std_logic lab=VDD}
C {devices/lab_pin.sym} 2560 -1540 0 1 {name=p256 sig_type=std_logic lab=VSS}
C {devices/lab_pin.sym} 2560 -1520 0 1 {name=p257 sig_type=std_logic lab=BLB10}
C {devices/lab_pin.sym} 2560 -1500 0 1 {name=p258 sig_type=std_logic lab=BL9}
C {devices/lab_pin.sym} 2560 -1480 0 1 {name=p259 sig_type=std_logic lab=BLB8}
C {devices/lab_pin.sym} 2560 -1460 0 1 {name=p260 sig_type=std_logic lab=BL13}
C {devices/lab_pin.sym} 2560 -1440 0 1 {name=p261 sig_type=std_logic lab=BL12}
C {devices/lab_pin.sym} 2560 -1420 0 1 {name=p262 sig_type=std_logic lab=BLB12}
C {devices/lab_pin.sym} 2560 -1400 0 1 {name=p263 sig_type=std_logic lab=BLB9}
C {devices/lab_pin.sym} 2560 -1380 0 1 {name=p264 sig_type=std_logic lab=BL11}
C {devices/lab_pin.sym} 2560 -1360 0 1 {name=p265 sig_type=std_logic lab=BL10}
C {devices/lab_pin.sym} 2560 -1340 0 1 {name=p266 sig_type=std_logic lab=BL14}
C {devices/lab_pin.sym} 2560 -1320 0 1 {name=p267 sig_type=std_logic lab=BLB14}
C {devices/lab_pin.sym} 2560 -1300 0 1 {name=p268 sig_type=std_logic lab=BLB13}
C {devices/lab_pin.sym} 2560 -1280 0 1 {name=p269 sig_type=std_logic lab=BLB15}
C {devices/lab_pin.sym} 2560 -1260 0 1 {name=p270 sig_type=std_logic lab=BL15}
C {devices/lab_pin.sym} 2560 -1240 0 1 {name=p271 sig_type=std_logic lab=BLB11}
C {devices/lab_pin.sym} 2560 -1220 0 1 {name=p272 sig_type=std_logic lab=BL8}
C {devices/lab_pin.sym} 2560 -1200 0 1 {name=p273 sig_type=std_logic lab=BL5}
C {devices/lab_pin.sym} 2560 -1180 0 1 {name=p274 sig_type=std_logic lab=BLB4}
C {devices/lab_pin.sym} 2560 -1160 0 1 {name=p275 sig_type=std_logic lab=BL1}
C {devices/lab_pin.sym} 2560 -1140 0 1 {name=p276 sig_type=std_logic lab=BL4}
C {devices/lab_pin.sym} 2560 -1120 0 1 {name=p277 sig_type=std_logic lab=BLB3}
C {devices/lab_pin.sym} 2560 -1100 0 1 {name=p278 sig_type=std_logic lab=BLB0}
C {devices/lab_pin.sym} 2560 -1080 0 1 {name=p279 sig_type=std_logic lab=BL3}
C {devices/lab_pin.sym} 2560 -1060 0 1 {name=p280 sig_type=std_logic lab=BLB7}
C {devices/lab_pin.sym} 2560 -1040 0 1 {name=p281 sig_type=std_logic lab=BLB2}
C {devices/lab_pin.sym} 2560 -1020 0 1 {name=p282 sig_type=std_logic lab=BL7}
C {devices/lab_pin.sym} 2560 -1000 0 1 {name=p283 sig_type=std_logic lab=BLB6}
C {devices/lab_pin.sym} 2560 -980 0 1 {name=p284 sig_type=std_logic lab=BL6}
C {devices/lab_pin.sym} 2560 -960 0 1 {name=p285 sig_type=std_logic lab=BLB5}
C {devices/lab_pin.sym} 2560 -940 0 1 {name=p286 sig_type=std_logic lab=BL2}
C {devices/lab_pin.sym} 2560 -920 0 1 {name=p287 sig_type=std_logic lab=BLB1}
C {devices/lab_pin.sym} 2560 -900 0 1 {name=p288 sig_type=std_logic lab=BL0}
C {devices/lab_pin.sym} 560 -2650 0 1 {name=p289 sig_type=std_logic lab=VDD}
C {devices/lab_pin.sym} 560 -2630 0 1 {name=p290 sig_type=std_logic lab=VSS}
C {devices/lab_pin.sym} 560 -2610 0 1 {name=p291 sig_type=std_logic lab=BLB10}
C {devices/lab_pin.sym} 560 -2590 0 1 {name=p292 sig_type=std_logic lab=BL9}
C {devices/lab_pin.sym} 560 -2570 0 1 {name=p293 sig_type=std_logic lab=BLB8}
C {devices/lab_pin.sym} 560 -2550 0 1 {name=p294 sig_type=std_logic lab=BL13}
C {devices/lab_pin.sym} 560 -2530 0 1 {name=p295 sig_type=std_logic lab=BL12}
C {devices/lab_pin.sym} 560 -2510 0 1 {name=p296 sig_type=std_logic lab=BLB12}
C {devices/lab_pin.sym} 560 -2490 0 1 {name=p297 sig_type=std_logic lab=BLB9}
C {devices/lab_pin.sym} 560 -2470 0 1 {name=p298 sig_type=std_logic lab=BL11}
C {devices/lab_pin.sym} 560 -2450 0 1 {name=p299 sig_type=std_logic lab=BL10}
C {devices/lab_pin.sym} 560 -2430 0 1 {name=p300 sig_type=std_logic lab=BL14}
C {devices/lab_pin.sym} 560 -2410 0 1 {name=p301 sig_type=std_logic lab=BLB14}
C {devices/lab_pin.sym} 560 -2390 0 1 {name=p302 sig_type=std_logic lab=BLB13}
C {devices/lab_pin.sym} 560 -2370 0 1 {name=p303 sig_type=std_logic lab=BLB15}
C {devices/lab_pin.sym} 560 -2350 0 1 {name=p304 sig_type=std_logic lab=BL15}
C {devices/lab_pin.sym} 560 -2330 0 1 {name=p305 sig_type=std_logic lab=BLB11}
C {devices/lab_pin.sym} 560 -2310 0 1 {name=p306 sig_type=std_logic lab=BL8}
C {devices/lab_pin.sym} 560 -2290 0 1 {name=p307 sig_type=std_logic lab=BL5}
C {devices/lab_pin.sym} 560 -2270 0 1 {name=p308 sig_type=std_logic lab=BLB4}
C {devices/lab_pin.sym} 560 -2250 0 1 {name=p309 sig_type=std_logic lab=BL1}
C {devices/lab_pin.sym} 560 -2230 0 1 {name=p310 sig_type=std_logic lab=BL4}
C {devices/lab_pin.sym} 560 -2210 0 1 {name=p311 sig_type=std_logic lab=BLB3}
C {devices/lab_pin.sym} 560 -2190 0 1 {name=p312 sig_type=std_logic lab=BLB0}
C {devices/lab_pin.sym} 560 -2170 0 1 {name=p313 sig_type=std_logic lab=BL3}
C {devices/lab_pin.sym} 560 -2150 0 1 {name=p314 sig_type=std_logic lab=BLB7}
C {devices/lab_pin.sym} 560 -2130 0 1 {name=p315 sig_type=std_logic lab=BLB2}
C {devices/lab_pin.sym} 560 -2110 0 1 {name=p316 sig_type=std_logic lab=BL7}
C {devices/lab_pin.sym} 560 -2090 0 1 {name=p317 sig_type=std_logic lab=BLB6}
C {devices/lab_pin.sym} 560 -2070 0 1 {name=p318 sig_type=std_logic lab=BL6}
C {devices/lab_pin.sym} 560 -2050 0 1 {name=p319 sig_type=std_logic lab=BLB5}
C {devices/lab_pin.sym} 560 -2030 0 1 {name=p320 sig_type=std_logic lab=BL2}
C {devices/lab_pin.sym} 560 -2010 0 1 {name=p321 sig_type=std_logic lab=BLB1}
C {devices/lab_pin.sym} 560 -1990 0 1 {name=p322 sig_type=std_logic lab=BL0}
C {devices/iopin.sym} 520 -2650 0 1 {name=p323 lab=VDD}
C {devices/iopin.sym} 520 -2630 0 1 {name=p324 lab=VSS}
C {devices/iopin.sym} 520 -2610 0 1 {name=p325 lab=BLB10}
C {devices/iopin.sym} 520 -2590 0 1 {name=p326 lab=BL9}
C {devices/iopin.sym} 520 -2570 0 1 {name=p327 lab=BLB8}
C {devices/iopin.sym} 520 -2550 0 1 {name=p328 lab=BL13}
C {devices/iopin.sym} 520 -2530 0 1 {name=p329 lab=BL12}
C {devices/iopin.sym} 520 -2510 0 1 {name=p330 lab=BLB12}
C {devices/iopin.sym} 520 -2490 0 1 {name=p331 lab=BLB9}
C {devices/iopin.sym} 520 -2470 0 1 {name=p332 lab=BL11}
C {devices/iopin.sym} 520 -2450 0 1 {name=p333 lab=BL10}
C {devices/iopin.sym} 520 -2430 0 1 {name=p334 lab=BL14}
C {devices/iopin.sym} 520 -2410 0 1 {name=p335 lab=BLB14}
C {devices/iopin.sym} 520 -2390 0 1 {name=p336 lab=BLB13}
C {devices/iopin.sym} 520 -2370 0 1 {name=p337 lab=BLB15}
C {devices/iopin.sym} 520 -2350 0 1 {name=p338 lab=BL15}
C {devices/iopin.sym} 520 -2330 0 1 {name=p339 lab=BLB11}
C {devices/iopin.sym} 520 -2310 0 1 {name=p340 lab=BL8}
C {devices/iopin.sym} 520 -2290 0 1 {name=p341 lab=BL5}
C {devices/iopin.sym} 520 -2270 0 1 {name=p357 lab=BLB4}
C {devices/iopin.sym} 520 -2250 0 1 {name=p358 lab=BL1}
C {devices/iopin.sym} 520 -2230 0 1 {name=p359 lab=BL4}
C {devices/iopin.sym} 520 -2210 0 1 {name=p360 lab=BLB3}
C {devices/iopin.sym} 520 -2190 0 1 {name=p361 lab=BLB0}
C {devices/iopin.sym} 520 -2170 0 1 {name=p362 lab=BL3}
C {devices/iopin.sym} 520 -2150 0 1 {name=p363 lab=BLB7}
C {devices/iopin.sym} 520 -2130 0 1 {name=p364 lab=BLB2}
C {devices/iopin.sym} 520 -2110 0 1 {name=p365 lab=BL7}
C {devices/iopin.sym} 520 -2090 0 1 {name=p366 lab=BLB6}
C {devices/iopin.sym} 520 -2070 0 1 {name=p367 lab=BL6}
C {devices/iopin.sym} 520 -2050 0 1 {name=p368 lab=BLB5}
C {devices/iopin.sym} 520 -2030 0 1 {name=p369 lab=BL2}
C {devices/iopin.sym} 520 -2010 0 1 {name=p370 lab=BLB1}
C {devices/iopin.sym} 520 -1990 0 1 {name=p371 lab=BL0}
